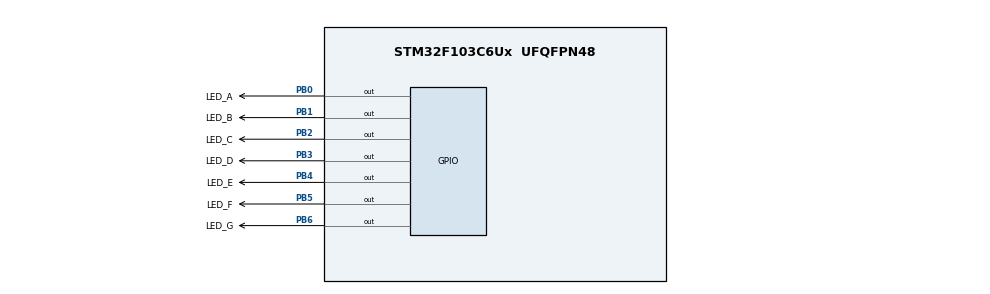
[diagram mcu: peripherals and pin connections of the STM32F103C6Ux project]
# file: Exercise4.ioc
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Mcu.Family=STM32F1
Mcu.Name=STM32F103C6Ux
Mcu.Package=UFQFPN48
NVIC.PriorityGroup=NVIC_PRIORITYGROUP_4
PB0.GPIO_Label=LED_A
PB0.Signal=GPIO_Output
PB1.GPIO_Label=LED_B
PB1.Signal=GPIO_Output
PB2.GPIO_Label=LED_C
PB2.Signal=GPIO_Output
PB3.GPIO_Label=LED_D
PB3.Signal=GPIO_Output
PB4.GPIO_Label=LED_E
PB4.Signal=GPIO_Output
PB5.GPIO_Label=LED_F
PB5.Signal=GPIO_Output
PB6.GPIO_Label=LED_G
PB6.Signal=GPIO_Output
ProjectManager.HeapSize=0x200
ProjectManager.StackSize=0x400
ProjectManager.TargetToolchain=STM32CubeIDE
RCC.APB1Freq_Value=8000000
RCC.APB2Freq_Value=8000000
board=custom

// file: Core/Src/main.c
/* USER CODE BEGIN Header */
/**
  ******************************************************************************
  * @file           : main.c
  * @brief          : Main program body
  ******************************************************************************
  * @attention
  *
  * Copyright (c) 2023 STMicroelectronics.
  * All rights reserved.
  *
  * This software is licensed under terms that can be found in the LICENSE file
  * in the root directory of this software component.
  * If no LICENSE file comes with this software, it is provided AS-IS.
  *
  ******************************************************************************
  */
/* USER CODE END Header */
#include "main.h"

void SystemClock_Config(void);
static void MX_GPIO_Init(void);

void display7SEG1(int num){
	switch(num){
		case 0:
			HAL_GPIO_WritePin ( LED_A1_GPIO_Port , LED_A1_Pin , GPIO_PIN_RESET ) ;
			HAL_GPIO_WritePin ( LED_B1_GPIO_Port , LED_B1_Pin , GPIO_PIN_RESET ) ;
			HAL_GPIO_WritePin ( LED_C1_GPIO_Port , LED_C1_Pin , GPIO_PIN_RESET ) ;
			HAL_GPIO_WritePin ( LED_D1_GPIO_Port , LED_D1_Pin , GPIO_PIN_RESET ) ;
			HAL_GPIO_WritePin ( LED_E1_GPIO_Port , LED_E1_Pin , GPIO_PIN_RESET ) ;
			HAL_GPIO_WritePin ( LED_F1_GPIO_Port , LED_F1_Pin , GPIO_PIN_RESET ) ;
			HAL_GPIO_WritePin ( LED_G1_GPIO_Port , LED_G1_Pin , GPIO_PIN_SET ) ;
			break;
		case 1:
			HAL_GPIO_WritePin ( LED_A1_GPIO_Port , LED_A1_Pin , GPIO_PIN_SET ) ;
			HAL_GPIO_WritePin ( LED_B1_GPIO_Port , LED_B1_Pin , GPIO_PIN_RESET ) ;
			HAL_GPIO_WritePin ( LED_C1_GPIO_Port , LED_C1_Pin , GPIO_PIN_RESET ) ;
			HAL_GPIO_WritePin ( LED_D1_GPIO_Port , LED_D1_Pin , GPIO_PIN_SET ) ;
			HAL_GPIO_WritePin ( LED_E1_GPIO_Port , LED_E1_Pin , GPIO_PIN_SET ) ;
			HAL_GPIO_WritePin ( LED_F1_GPIO_Port , LED_F1_Pin , GPIO_PIN_SET ) ;
			HAL_GPIO_WritePin ( LED_G1_GPIO_Port , LED_G1_Pin , GPIO_PIN_SET ) ;
			break;
		case 2:
			HAL_GPIO_WritePin ( LED_A1_GPIO_Port , LED_A1_Pin , GPIO_PIN_RESET ) ;
			HAL_GPIO_WritePin ( LED_B1_GPIO_Port , LED_B1_Pin , GPIO_PIN_RESET ) ;
			HAL_GPIO_WritePin ( LED_C1_GPIO_Port , LED_C1_Pin , GPIO_PIN_SET ) ;
			HAL_GPIO_WritePin ( LED_D1_GPIO_Port , LED_D1_Pin , GPIO_PIN_RESET ) ;
			HAL_GPIO_WritePin ( LED_E1_GPIO_Port , LED_E1_Pin , GPIO_PIN_RESET ) ;
			HAL_GPIO_WritePin ( LED_F1_GPIO_Port , LED_F1_Pin , GPIO_PIN_SET ) ;
			HAL_GPIO_WritePin ( LED_G1_GPIO_Port , LED_G1_Pin , GPIO_PIN_RESET ) ;
			break;
		case 3:
			HAL_GPIO_WritePin ( LED_A1_GPIO_Port , LED_A1_Pin , GPIO_PIN_RESET ) ;
			HAL_GPIO_WritePin ( LED_B1_GPIO_Port , LED_B1_Pin , GPIO_PIN_RESET ) ;
			HAL_GPIO_WritePin ( LED_C1_GPIO_Port , LED_C1_Pin , GPIO_PIN_RESET ) ;
			HAL_GPIO_WritePin ( LED_D1_GPIO_Port , LED_D1_Pin , GPIO_PIN_RESET ) ;
			HAL_GPIO_WritePin ( LED_E1_GPIO_Port , LED_E1_Pin , GPIO_PIN_SET ) ;
			HAL_GPIO_WritePin ( LED_F1_GPIO_Port , LED_F1_Pin , GPIO_PIN_SET ) ;
			HAL_GPIO_WritePin ( LED_G1_GPIO_Port , LED_G1_Pin , GPIO_PIN_RESET ) ;
			break;
		case 4:
			HAL_GPIO_WritePin ( LED_A1_GPIO_Port , LED_A1_Pin , GPIO_PIN_SET ) ;
			HAL_GPIO_WritePin ( LED_B1_GPIO_Port , LED_B1_Pin , GPIO_PIN_RESET ) ;
			HAL_GPIO_WritePin ( LED_C1_GPIO_Port , LED_C1_Pin , GPIO_PIN_RESET ) ;
			HAL_GPIO_WritePin ( LED_D1_GPIO_Port , LED_D1_Pin , GPIO_PIN_SET ) ;
			HAL_GPIO_WritePin ( LED_E1_GPIO_Port , LED_E1_Pin , GPIO_PIN_SET ) ;
			HAL_GPIO_WritePin ( LED_F1_GPIO_Port , LED_F1_Pin , GPIO_PIN_RESET ) ;
			HAL_GPIO_WritePin ( LED_G1_GPIO_Port , LED_G1_Pin , GPIO_PIN_RESET ) ;
			break;
		case 5:
			HAL_GPIO_WritePin ( LED_A1_GPIO_Port , LED_A1_Pin , GPIO_PIN_RESET ) ;
			HAL_GPIO_WritePin ( LED_B1_GPIO_Port , LED_B1_Pin , GPIO_PIN_SET ) ;
			HAL_GPIO_WritePin ( LED_C1_GPIO_Port , LED_C1_Pin , GPIO_PIN_RESET ) ;
			HAL_GPIO_WritePin ( LED_D1_GPIO_Port , LED_D1_Pin , GPIO_PIN_RESET ) ;
			HAL_GPIO_WritePin ( LED_E1_GPIO_Port , LED_E1_Pin , GPIO_PIN_SET ) ;
			HAL_GPIO_WritePin ( LED_F1_GPIO_Port , LED_F1_Pin , GPIO_PIN_RESET ) ;
			HAL_GPIO_WritePin ( LED_G1_GPIO_Port , LED_G1_Pin , GPIO_PIN_RESET ) ;
			break;
		case 6:
			HAL_GPIO_WritePin ( LED_A1_GPIO_Port , LED_A1_Pin , GPIO_PIN_RESET ) ;
			HAL_GPIO_WritePin ( LED_B1_GPIO_Port , LED_B1_Pin , GPIO_PIN_SET ) ;
			HAL_GPIO_WritePin ( LED_C1_GPIO_Port , LED_C1_Pin , GPIO_PIN_RESET ) ;
			HAL_GPIO_WritePin ( LED_D1_GPIO_Port , LED_D1_Pin , GPIO_PIN_RESET ) ;
			HAL_GPIO_WritePin ( LED_E1_GPIO_Port , LED_E1_Pin , GPIO_PIN_RESET ) ;
			HAL_GPIO_WritePin ( LED_F1_GPIO_Port , LED_F1_Pin , GPIO_PIN_RESET ) ;
			HAL_GPIO_WritePin ( LED_G1_GPIO_Port , LED_G1_Pin , GPIO_PIN_RESET ) ;
			break;
		case 7:
			HAL_GPIO_WritePin ( LED_A1_GPIO_Port , LED_A1_Pin , GPIO_PIN_RESET ) ;
			HAL_GPIO_WritePin ( LED_B1_GPIO_Port , LED_B1_Pin , GPIO_PIN_RESET ) ;
			HAL_GPIO_WritePin ( LED_C1_GPIO_Port , LED_C1_Pin , GPIO_PIN_RESET ) ;
			HAL_GPIO_WritePin ( LED_D1_GPIO_Port , LED_D1_Pin , GPIO_PIN_SET ) ;
			HAL_GPIO_WritePin ( LED_E1_GPIO_Port , LED_E1_Pin , GPIO_PIN_SET ) ;
			HAL_GPIO_WritePin ( LED_F1_GPIO_Port , LED_F1_Pin , GPIO_PIN_SET ) ;
			HAL_GPIO_WritePin ( LED_G1_GPIO_Port , LED_G1_Pin , GPIO_PIN_SET ) ;
			break;
		case 8:
			HAL_GPIO_WritePin ( LED_A1_GPIO_Port , LED_A1_Pin , GPIO_PIN_RESET ) ;
			HAL_GPIO_WritePin ( LED_B1_GPIO_Port , LED_B1_Pin , GPIO_PIN_RESET ) ;
			HAL_GPIO_WritePin ( LED_C1_GPIO_Port , LED_C1_Pin , GPIO_PIN_RESET ) ;
			HAL_GPIO_WritePin ( LED_D1_GPIO_Port , LED_D1_Pin , GPIO_PIN_RESET ) ;
			HAL_GPIO_WritePin ( LED_E1_GPIO_Port , LED_E1_Pin , GPIO_PIN_RESET ) ;
			HAL_GPIO_WritePin ( LED_F1_GPIO_Port , LED_F1_Pin , GPIO_PIN_RESET ) ;
			HAL_GPIO_WritePin ( LED_G1_GPIO_Port , LED_G1_Pin , GPIO_PIN_RESET ) ;
			break;
		case 9:
			HAL_GPIO_WritePin ( LED_A1_GPIO_Port , LED_A1_Pin , GPIO_PIN_RESET ) ;
			HAL_GPIO_WritePin ( LED_B1_GPIO_Port , LED_B1_Pin , GPIO_PIN_RESET ) ;
			HAL_GPIO_WritePin ( LED_C1_GPIO_Port , LED_C1_Pin , GPIO_PIN_RESET ) ;
			HAL_GPIO_WritePin ( LED_D1_GPIO_Port , LED_D1_Pin , GPIO_PIN_RESET ) ;
			HAL_GPIO_WritePin ( LED_E1_GPIO_Port , LED_E1_Pin , GPIO_PIN_SET ) ;
			HAL_GPIO_WritePin ( LED_F1_GPIO_Port , LED_F1_Pin , GPIO_PIN_RESET ) ;
			HAL_GPIO_WritePin ( LED_G1_GPIO_Port , LED_G1_Pin , GPIO_PIN_RESET ) ;
			break;
		default:
			break;
	}
}
void display7SEG2(int num){
	switch(num){
		case 0:
			HAL_GPIO_WritePin ( LED_A2_GPIO_Port , LED_A2_Pin , GPIO_PIN_RESET ) ;
			HAL_GPIO_WritePin ( LED_B2_GPIO_Port , LED_B2_Pin , GPIO_PIN_RESET ) ;
			HAL_GPIO_WritePin ( LED_C2_GPIO_Port , LED_C2_Pin , GPIO_PIN_RESET ) ;
			HAL_GPIO_WritePin ( LED_D2_GPIO_Port , LED_D2_Pin , GPIO_PIN_RESET ) ;
			HAL_GPIO_WritePin ( LED_E2_GPIO_Port , LED_E2_Pin , GPIO_PIN_RESET ) ;
			HAL_GPIO_WritePin ( LED_F2_GPIO_Port , LED_F2_Pin , GPIO_PIN_RESET ) ;
			HAL_GPIO_WritePin ( LED_G2_GPIO_Port , LED_G2_Pin , GPIO_PIN_SET ) ;
			break;
		case 1:
			HAL_GPIO_WritePin ( LED_A2_GPIO_Port , LED_A2_Pin , GPIO_PIN_SET ) ;
			HAL_GPIO_WritePin ( LED_B2_GPIO_Port , LED_B2_Pin , GPIO_PIN_RESET ) ;
			HAL_GPIO_WritePin ( LED_C2_GPIO_Port , LED_C2_Pin , GPIO_PIN_RESET ) ;
			HAL_GPIO_WritePin ( LED_D2_GPIO_Port , LED_D2_Pin , GPIO_PIN_SET ) ;
			HAL_GPIO_WritePin ( LED_E2_GPIO_Port , LED_E2_Pin , GPIO_PIN_SET ) ;
			HAL_GPIO_WritePin ( LED_F2_GPIO_Port , LED_F2_Pin , GPIO_PIN_SET ) ;
			HAL_GPIO_WritePin ( LED_G2_GPIO_Port , LED_G2_Pin , GPIO_PIN_SET ) ;
			break;
		case 2:
			HAL_GPIO_WritePin ( LED_A2_GPIO_Port , LED_A2_Pin , GPIO_PIN_RESET ) ;
			HAL_GPIO_WritePin ( LED_B2_GPIO_Port , LED_B2_Pin , GPIO_PIN_RESET ) ;
			HAL_GPIO_WritePin ( LED_C2_GPIO_Port , LED_C2_Pin , GPIO_PIN_SET ) ;
			HAL_GPIO_WritePin ( LED_D2_GPIO_Port , LED_D2_Pin , GPIO_PIN_RESET ) ;
			HAL_GPIO_WritePin ( LED_E2_GPIO_Port , LED_E2_Pin , GPIO_PIN_RESET ) ;
			HAL_GPIO_WritePin ( LED_F2_GPIO_Port , LED_F2_Pin , GPIO_PIN_SET ) ;
			HAL_GPIO_WritePin ( LED_G2_GPIO_Port , LED_G2_Pin , GPIO_PIN_RESET ) ;
			break;
		case 3:
			HAL_GPIO_WritePin ( LED_A2_GPIO_Port , LED_A2_Pin , GPIO_PIN_RESET ) ;
			HAL_GPIO_WritePin ( LED_B2_GPIO_Port , LED_B2_Pin , GPIO_PIN_RESET ) ;
			HAL_GPIO_WritePin ( LED_C2_GPIO_Port , LED_C2_Pin , GPIO_PIN_RESET ) ;
			HAL_GPIO_WritePin ( LED_D2_GPIO_Port , LED_D2_Pin , GPIO_PIN_RESET ) ;
			HAL_GPIO_WritePin ( LED_E2_GPIO_Port , LED_E2_Pin , GPIO_PIN_SET ) ;
			HAL_GPIO_WritePin ( LED_F2_GPIO_Port , LED_F2_Pin , GPIO_PIN_SET ) ;
			HAL_GPIO_WritePin ( LED_G2_GPIO_Port , LED_G2_Pin , GPIO_PIN_RESET ) ;
			break;
		case 4:
			HAL_GPIO_WritePin ( LED_A2_GPIO_Port , LED_A2_Pin , GPIO_PIN_SET ) ;
			HAL_GPIO_WritePin ( LED_B2_GPIO_Port , LED_B2_Pin , GPIO_PIN_RESET ) ;
			HAL_GPIO_WritePin ( LED_C2_GPIO_Port , LED_C2_Pin , GPIO_PIN_RESET ) ;
			HAL_GPIO_WritePin ( LED_D2_GPIO_Port , LED_D2_Pin , GPIO_PIN_SET ) ;
			HAL_GPIO_WritePin ( LED_E2_GPIO_Port , LED_E2_Pin , GPIO_PIN_SET ) ;
			HAL_GPIO_WritePin ( LED_F2_GPIO_Port , LED_F2_Pin , GPIO_PIN_RESET ) ;
			HAL_GPIO_WritePin ( LED_G2_GPIO_Port , LED_G2_Pin , GPIO_PIN_RESET ) ;
			break;
		case 5:
			HAL_GPIO_WritePin ( LED_A2_GPIO_Port , LED_A2_Pin , GPIO_PIN_RESET ) ;
			HAL_GPIO_WritePin ( LED_B2_GPIO_Port , LED_B2_Pin , GPIO_PIN_SET ) ;
			HAL_GPIO_WritePin ( LED_C2_GPIO_Port , LED_C2_Pin , GPIO_PIN_RESET ) ;
			HAL_GPIO_WritePin ( LED_D2_GPIO_Port , LED_D2_Pin , GPIO_PIN_RESET ) ;
			HAL_GPIO_WritePin ( LED_E2_GPIO_Port , LED_E2_Pin , GPIO_PIN_SET ) ;
			HAL_GPIO_WritePin ( LED_F2_GPIO_Port , LED_F2_Pin , GPIO_PIN_RESET ) ;
			HAL_GPIO_WritePin ( LED_G2_GPIO_Port , LED_G2_Pin , GPIO_PIN_RESET ) ;
			break;
		case 6:
			HAL_GPIO_WritePin ( LED_A2_GPIO_Port , LED_A2_Pin , GPIO_PIN_RESET ) ;
			HAL_GPIO_WritePin ( LED_B2_GPIO_Port , LED_B2_Pin , GPIO_PIN_SET ) ;
			HAL_GPIO_WritePin ( LED_C2_GPIO_Port , LED_C2_Pin , GPIO_PIN_RESET ) ;
			HAL_GPIO_WritePin ( LED_D2_GPIO_Port , LED_D2_Pin , GPIO_PIN_RESET ) ;
			HAL_GPIO_WritePin ( LED_E2_GPIO_Port , LED_E2_Pin , GPIO_PIN_RESET ) ;
			HAL_GPIO_WritePin ( LED_F2_GPIO_Port , LED_F2_Pin , GPIO_PIN_RESET ) ;
			HAL_GPIO_WritePin ( LED_G2_GPIO_Port , LED_G2_Pin , GPIO_PIN_RESET ) ;
			break;
		case 7:
			HAL_GPIO_WritePin ( LED_A2_GPIO_Port , LED_A2_Pin , GPIO_PIN_RESET ) ;
			HAL_GPIO_WritePin ( LED_B2_GPIO_Port , LED_B2_Pin , GPIO_PIN_RESET ) ;
			HAL_GPIO_WritePin ( LED_C2_GPIO_Port , LED_C2_Pin , GPIO_PIN_RESET ) ;
			HAL_GPIO_WritePin ( LED_D2_GPIO_Port , LED_D2_Pin , GPIO_PIN_SET ) ;
			HAL_GPIO_WritePin ( LED_E2_GPIO_Port , LED_E2_Pin , GPIO_PIN_SET ) ;
			HAL_GPIO_WritePin ( LED_F2_GPIO_Port , LED_F2_Pin , GPIO_PIN_SET ) ;
			HAL_GPIO_WritePin ( LED_G2_GPIO_Port , LED_G2_Pin , GPIO_PIN_SET ) ;
			break;
		case 8:
			HAL_GPIO_WritePin ( LED_A2_GPIO_Port , LED_A2_Pin , GPIO_PIN_RESET ) ;
			HAL_GPIO_WritePin ( LED_B2_GPIO_Port , LED_B2_Pin , GPIO_PIN_RESET ) ;
			HAL_GPIO_WritePin ( LED_C2_GPIO_Port , LED_C2_Pin , GPIO_PIN_RESET ) ;
			HAL_GPIO_WritePin ( LED_D2_GPIO_Port , LED_D2_Pin , GPIO_PIN_RESET ) ;
			HAL_GPIO_WritePin ( LED_E2_GPIO_Port , LED_E2_Pin , GPIO_PIN_RESET ) ;
			HAL_GPIO_WritePin ( LED_F2_GPIO_Port , LED_F2_Pin , GPIO_PIN_RESET ) ;
			HAL_GPIO_WritePin ( LED_G2_GPIO_Port , LED_G2_Pin , GPIO_PIN_RESET ) ;
			break;
		case 9:
			HAL_GPIO_WritePin ( LED_A2_GPIO_Port , LED_A2_Pin , GPIO_PIN_RESET ) ;
			HAL_GPIO_WritePin ( LED_B2_GPIO_Port , LED_B2_Pin , GPIO_PIN_RESET ) ;
			HAL_GPIO_WritePin ( LED_C2_GPIO_Port , LED_C2_Pin , GPIO_PIN_RESET ) ;
			HAL_GPIO_WritePin ( LED_D2_GPIO_Port , LED_D2_Pin , GPIO_PIN_RESET ) ;
			HAL_GPIO_WritePin ( LED_E2_GPIO_Port , LED_E2_Pin , GPIO_PIN_SET ) ;
			HAL_GPIO_WritePin ( LED_F2_GPIO_Port , LED_F2_Pin , GPIO_PIN_RESET ) ;
			HAL_GPIO_WritePin ( LED_G2_GPIO_Port , LED_G2_Pin , GPIO_PIN_RESET ) ;
			break;
		default:
			break;
	}
}
int main(void)
{

  /* MCU Configuration--------------------------------------------------------*/

  /* Reset of all peripherals, Initializes the Flash interface and the Systick. */
  HAL_Init();

  /* Configure the system clock */
  SystemClock_Config();

  /* Initialize all configured peripherals */
  MX_GPIO_Init();

  /* Infinite loop */
  /* USER CODE BEGIN WHILE */
  int a = 5, b = 5;
       while (1)
       {
         /* USER CODE END WHILE */
     	  if(a > 2){
     		  display7SEG1(a);
     		  display7SEG2(a-2);
     		  a--;
     	  }else if(a > 0){
     		  HAL_GPIO_WritePin ( LED_GREEN2_GPIO_Port , LED_GREEN2_Pin , GPIO_PIN_SET ) ;
     		  HAL_GPIO_WritePin ( LED_YELLOW2_GPIO_Port , LED_YELLOW2_Pin , GPIO_PIN_RESET ) ;
     		  display7SEG1(a);
     		  display7SEG2(a);
     		  a--;
     	  }else{
     		  HAL_GPIO_WritePin ( LED_YELLOW2_GPIO_Port , LED_YELLOW2_Pin , GPIO_PIN_SET ) ;
     		  HAL_GPIO_WritePin ( LED_RED2_GPIO_Port , LED_RED2_Pin , GPIO_PIN_RESET ) ;
     		  HAL_GPIO_WritePin ( LED_RED1_GPIO_Port , LED_RED1_Pin , GPIO_PIN_SET ) ;
     		  if(b > 2){
     			  HAL_GPIO_WritePin ( LED_GREEN1_GPIO_Port , LED_GREEN1_Pin , GPIO_PIN_RESET ) ;
     			  display7SEG1(b - 2);
     			  display7SEG2(b);
     			  b--;
     		  }else if(b > 0){
     			  HAL_GPIO_WritePin ( LED_GREEN1_GPIO_Port , LED_GREEN1_Pin , GPIO_PIN_SET ) ;
     			  HAL_GPIO_WritePin ( LED_YELLOW1_GPIO_Port , LED_YELLOW1_Pin , GPIO_PIN_RESET ) ;
     			  display7SEG1(b);
     			  display7SEG2(b);
     			  b--;
     		  }else{
     			  a = 5; b = 5;
     			  HAL_GPIO_WritePin ( LED_YELLOW1_GPIO_Port , LED_YELLOW1_Pin , GPIO_PIN_SET ) ;
     			  HAL_GPIO_WritePin ( LED_RED1_GPIO_Port , LED_RED1_Pin , GPIO_PIN_RESET ) ;
     			  HAL_GPIO_WritePin ( LED_GREEN2_GPIO_Port , LED_GREEN2_Pin , GPIO_PIN_RESET ) ;
     			  HAL_GPIO_WritePin ( LED_RED2_GPIO_Port , LED_RED2_Pin , GPIO_PIN_SET ) ;
     			  display7SEG1(a);
     			  display7SEG2(a-2);
     			  a--;
     		  }
     	  }
         /* USER CODE BEGIN 3 */
     	  HAL_Delay(1000) ;
       }
  /* USER CODE END 3 */
}

void SystemClock_Config(void)
{
  RCC_OscInitTypeDef RCC_OscInitStruct = {0};
  RCC_ClkInitTypeDef RCC_ClkInitStruct = {0};

  /** Initializes the RCC Oscillators according to the specified parameters
  * in the RCC_OscInitTypeDef structure.
  */
  RCC_OscInitStruct.OscillatorType = RCC_OSCILLATORTYPE_HSI;
  RCC_OscInitStruct.HSIState = RCC_HSI_ON;
  RCC_OscInitStruct.HSICalibrationValue = RCC_HSICALIBRATION_DEFAULT;
  RCC_OscInitStruct.PLL.PLLState = RCC_PLL_NONE;
  if (HAL_RCC_OscConfig(&RCC_OscInitStruct) != HAL_OK)
  {
    Error_Handler();
  }

  /** Initializes the CPU, AHB and APB buses clocks
  */
  RCC_ClkInitStruct.ClockType = RCC_CLOCKTYPE_HCLK|RCC_CLOCKTYPE_SYSCLK
                              |RCC_CLOCKTYPE_PCLK1|RCC_CLOCKTYPE_PCLK2;
  RCC_ClkInitStruct.SYSCLKSource = RCC_SYSCLKSOURCE_HSI;
  RCC_ClkInitStruct.AHBCLKDivider = RCC_SYSCLK_DIV1;
  RCC_ClkInitStruct.APB1CLKDivider = RCC_HCLK_DIV1;
  RCC_ClkInitStruct.APB2CLKDivider = RCC_HCLK_DIV1;

  if (HAL_RCC_ClockConfig(&RCC_ClkInitStruct, FLASH_LATENCY_0) != HAL_OK)
  {
    Error_Handler();
  }
}

static void MX_GPIO_Init(void)
{
  GPIO_InitTypeDef GPIO_InitStruct = {0};

  /* GPIO Ports Clock Enable */
  __HAL_RCC_GPIOA_CLK_ENABLE();
  __HAL_RCC_GPIOB_CLK_ENABLE();

  /*Configure GPIO pin Output Level */
  HAL_GPIO_WritePin(GPIOA, LED_RED1_Pin|LED_GREEN2_Pin, GPIO_PIN_RESET);

  /*Configure GPIO pin Output Level */
  HAL_GPIO_WritePin(GPIOA, LED_YELLOW1_Pin|LED_GREEN1_Pin|LED_RED2_Pin|LED_YELLOW2_Pin, GPIO_PIN_SET);

  /*Configure GPIO pin Output Level */
  HAL_GPIO_WritePin(GPIOB, LED_A1_Pin|LED_B1_Pin|LED_C1_Pin|LED_D2_Pin
                          |LED_E2_Pin|LED_F2_Pin|LED_G2_Pin|LED_D1_Pin
                          |LED_E1_Pin|LED_F1_Pin|LED_G1_Pin|LED_A2_Pin
                          |LED_B2_Pin|LED_C2_Pin, GPIO_PIN_SET);

  /*Configure GPIO pins : LED_RED1_Pin LED_YELLOW1_Pin LED_GREEN1_Pin LED_RED2_Pin
                           LED_YELLOW2_Pin LED_GREEN2_Pin */
  GPIO_InitStruct.Pin = LED_RED1_Pin|LED_YELLOW1_Pin|LED_GREEN1_Pin|LED_RED2_Pin
                          |LED_YELLOW2_Pin|LED_GREEN2_Pin;
  GPIO_InitStruct.Mode = GPIO_MODE_OUTPUT_PP;
  GPIO_InitStruct.Pull = GPIO_NOPULL;
  GPIO_InitStruct.Speed = GPIO_SPEED_FREQ_LOW;
  HAL_GPIO_Init(GPIOA, &GPIO_InitStruct);

  /*Configure GPIO pins : LED_A1_Pin LED_B1_Pin LED_C1_Pin LED_D2_Pin
                           LED_E2_Pin LED_F2_Pin LED_G2_Pin LED_D1_Pin
                           LED_E1_Pin LED_F1_Pin LED_G1_Pin LED_A2_Pin
                           LED_B2_Pin LED_C2_Pin */
  GPIO_InitStruct.Pin = LED_A1_Pin|LED_B1_Pin|LED_C1_Pin|LED_D2_Pin
                          |LED_E2_Pin|LED_F2_Pin|LED_G2_Pin|LED_D1_Pin
                          |LED_E1_Pin|LED_F1_Pin|LED_G1_Pin|LED_A2_Pin
                          |LED_B2_Pin|LED_C2_Pin;
  GPIO_InitStruct.Mode = GPIO_MODE_OUTPUT_PP;
  GPIO_InitStruct.Pull = GPIO_NOPULL;
  GPIO_InitStruct.Speed = GPIO_SPEED_FREQ_LOW;
  HAL_GPIO_Init(GPIOB, &GPIO_InitStruct);

}

void Error_Handler(void)
{
  __disable_irq();
  while (1)
  {
  }
}
